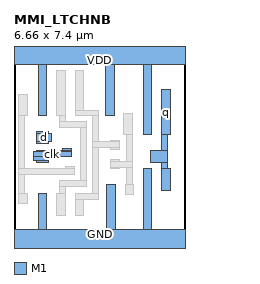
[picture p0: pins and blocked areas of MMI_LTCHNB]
MACRO MMI_LTCHNB
	CLASS CORE ;
	FOREIGN MMI_LTCHNB 0 0 ;
	SIZE 6.66 BY 7.4 ;
	SYMMETRY X Y ;
	SITE CORE1 ;
	PIN d
		DIRECTION input ;
		USE SIGNAL ;
		PORT
			LAYER M1 ;
			RECT 0.885 4.235 1.335 4.295 ;
			LAYER M1 ;
			RECT 0.885 3.895 1.475 4.235 ;
			LAYER M1 ;
			RECT 0.885 3.845 1.335 3.895 ;
		END
		AntennaGateArea 0.4968 ;
	END d
	PIN GND
		DIRECTION inout ;
		USE GROUND ;
		PORT
			LAYER M1 ;
			RECT 0.94 0.5 1.28 1.875 ;
			LAYER M1 ;
			RECT 3.61 0.5 3.95 2.24 ;
			LAYER M1 ;
			RECT 5.03 0.5 5.37 2.845 ;
			LAYER M1 ;
			RECT 0 -0.5 6.66 0.5 ;
		END
	END GND
	PIN q
		DIRECTION output ;
		USE SIGNAL ;
		PORT
			LAYER M1 ;
			RECT 5.75 4.18 6.09 5.94 ;
			LAYER M1 ;
			RECT 5.75 3.555 5.98 4.18 ;
			LAYER M1 ;
			RECT 5.325 3.105 5.98 3.555 ;
			LAYER M1 ;
			RECT 5.75 2.845 5.98 3.105 ;
			LAYER M1 ;
			RECT 5.75 2.005 6.09 2.845 ;
		END
		AntennaDiffArea 1.3248 ;
	END q
	PIN VDD
		DIRECTION inout ;
		USE POWER ;
		PORT
			LAYER M1 ;
			RECT 0 6.9 6.66 7.9 ;
			LAYER M1 ;
			RECT 0.94 4.91 1.28 6.9 ;
			LAYER M1 ;
			RECT 3.57 4.91 3.91 6.9 ;
			LAYER M1 ;
			RECT 5.03 4.18 5.37 6.9 ;
		END
	END VDD
	PIN clk
		DIRECTION input ;
		USE CLOCK ;
		PORT
			LAYER M1 ;
			RECT 1.9 3.555 2.24 3.66 ;
			LAYER M1 ;
			RECT 0.885 3.51 2.24 3.555 ;
			LAYER M1 ;
			RECT 0.75 3.325 2.24 3.51 ;
			LAYER M1 ;
			RECT 0.75 3.17 1.335 3.325 ;
			LAYER M1 ;
			RECT 1.9 3.32 2.24 3.325 ;
			LAYER M1 ;
			RECT 0.885 3.105 1.335 3.17 ;
		END
		AntennaGateArea 0.6552 ;
	END clk
	OBS
		LAYER M1 ;
		RECT 0.18 4.91 0.52 5.75 ;
		LAYER M1 ;
		RECT 1.66 4.91 2 6.67 ;
		LAYER M1 ;
		RECT 2.38 5.14 2.72 6.67 ;
		LAYER M1 ;
		RECT 2.38 4.91 3.29 5.14 ;
		LAYER M1 ;
		RECT 0.18 2.85 0.41 4.91 ;
		LAYER M1 ;
		RECT 1.77 4.68 2 4.91 ;
		LAYER M1 ;
		RECT 1.77 4.45 2.83 4.68 ;
		LAYER M1 ;
		RECT 2.02 2.85 2.36 2.96 ;
		LAYER M1 ;
		RECT 0.18 2.62 2.36 2.85 ;
		LAYER M1 ;
		RECT 0.18 1.875 0.41 2.62 ;
		LAYER M1 ;
		RECT 2.6 2.39 2.83 4.45 ;
		LAYER M1 ;
		RECT 1.77 2.16 2.83 2.39 ;
		LAYER M1 ;
		RECT 3.06 3.895 3.29 4.91 ;
		LAYER M1 ;
		RECT 4.27 4.18 4.61 5.02 ;
		LAYER M1 ;
		RECT 3.77 3.895 4.11 3.935 ;
		LAYER M1 ;
		RECT 3.06 3.665 4.11 3.895 ;
		LAYER M1 ;
		RECT 1.77 1.875 2 2.16 ;
		LAYER M1 ;
		RECT 3.06 1.875 3.29 3.665 ;
		LAYER M1 ;
		RECT 3.77 3.595 4.11 3.665 ;
		LAYER M1 ;
		RECT 3.76 3.145 4.1 3.205 ;
		LAYER M1 ;
		RECT 4.38 3.145 4.61 4.18 ;
		LAYER M1 ;
		RECT 3.76 2.915 4.61 3.145 ;
		LAYER M1 ;
		RECT 3.76 2.865 4.1 2.915 ;
		LAYER M1 ;
		RECT 4.38 2.24 4.61 2.915 ;
		LAYER M1 ;
		RECT 0.18 1.495 0.52 1.875 ;
		LAYER M1 ;
		RECT 1.66 1.035 2 1.875 ;
		LAYER M1 ;
		RECT 2.38 1.645 3.29 1.875 ;
		LAYER M1 ;
		RECT 2.38 1.035 2.72 1.645 ;
		LAYER M1 ;
		RECT 4.33 1.86 4.67 2.24 ;
	END
END MMI_LTCHNB
